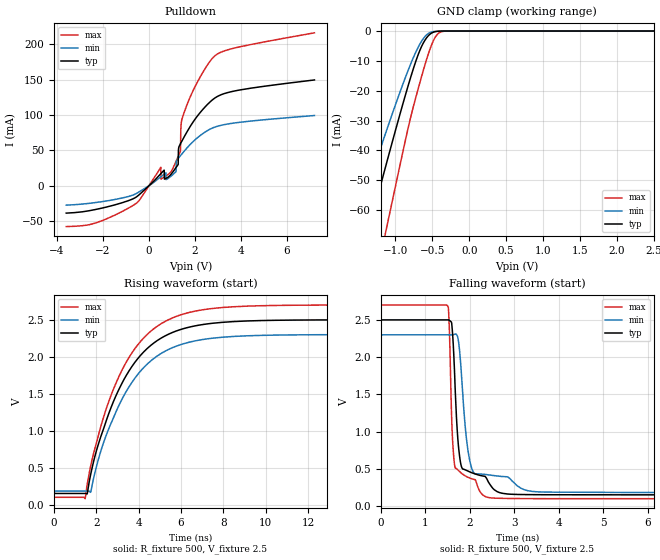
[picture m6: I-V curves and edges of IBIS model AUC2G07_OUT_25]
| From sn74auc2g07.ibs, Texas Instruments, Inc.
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[Model]   AUC2G07_OUT_25
Model_type  Open_drain
Enable   Active-Low
Vref =   2.5
Rref =   500
Cref =   30p
Vmeas =   1.25
| variable   typ   min   max
C_comp   2.87pF   2.41pF   3.25pF
| C_pulldown   5.35pF   1.05pF   13.60pF
| C_tri-state   2.87pF   2.41pF   3.25pF
[Temperature Range]   40   100   -40
| Ambient temperature   25   85   -40
[Voltage range]   2.5   2.3   2.7
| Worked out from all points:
|   slope of the pulldown table from 0 to 0.375 V, typ, clamps not added: 31 ohm
|   GND clamp passes 1 mA (typ) near -0.53 V on its own axis
|   rising waveform, R_fixture 500, V_fixture 2.5: 20-80 % time 2.22ns typ, 2.22ns min, 2.2ns max; typ from 0.154 V to 2.5 V
|   falling waveform, R_fixture 500, V_fixture 2.5: 20-80 % time 142ps typ, 202ps min, 95.6ps max; typ from 2.5 V to 0.154 V
[GND Clamp]
| AUC2G07_OUT_25
|   Voltage   I(typ)   I(min)   I(max)
-3.6V     -279.3mA   -228.7mA   -348mA
-1.585V   -87.68mA   -68.18mA   -119.7mA
-1.53V    -82.49mA   -63.96mA   -113.4mA
-1.34V    -64.62mA   -49.54mA   -91.44mA
-1.16V    -47.9mA    -36.19mA   -70.6mA
-1.11V    -43.3mA    -32.56mA   -64.8mA
-730mV    -10.56mA   -7.384mA   -22.79mA
-630mV    -4.374mA   -2.805mA   -13.86mA
-530mV    -1.024mA   -505.6uA   -5.921mA
-440mV    -130.5uA   -65.28uA   -1.345mA
-340mV    -7.443uA   -5.464uA   -72.36uA
2.5V      609.9pA    770.4pA    903.3pA
[Pulldown]
| AUC2G07_OUT_25
|   Voltage   I(typ)   I(min)   I(max)
-3.6V     -38.75mA   -27.46mA   -57.79mA
-1.19V    -24.29mA   -17.54mA   -36.85mA
515mV     17.02mA    12.57mA    25.99mA
520mV     17.2mA     12.7mA     9.298mA
930mV     15.04mA    12.66mA    18.59mA
1.27V     30.04mA    38.39mA    41.38mA
1.285V    51.79mA    39.01mA    42.52mA
1.37V     59.36mA    42.45mA    48.97mA
1.41V     61.79mA    44.06mA    89.97mA
1.645V    75.61mA    53.07mA    113.7mA
2.89V     124.5mA    83.14mA    184.2mA
7.2V      149.5mA    99.24mA    216.2mA
[Ramp]
| AUC2G07_OUT_25
| variable   typ   min   max
dV/dt_r   1.41/2.22E-09   1.28/2.22E-09   1.57/2.20E-09
dV/dt_f   1.41/1.45E-10   1.28/2.07E-10   1.56/9.72E-11
R_load = 500
[Rising Waveform]
| AUC2G07_OUT_25
R_fixture =   500
C_fixture =   0
L_fixture =   0
V_fixture =   2.5
V_fixture_min = 2.3
V_fixture_max = 2.7
|   Time   V(typ)   V(min)   V(max)
0s        154.5mV    186.3mV    102.6mV
1.475ns   154.2mV    186.3mV    83.61mV
1.575ns   149.7mV    186.3mV    275.2mV
1.74ns    412.2mV    176mV      527mV
2.21ns    916.1mV    720.5mV    1.052V
3.165ns   1.614V     1.399V     1.79V
4.255ns   2.069V     1.858V     2.259V
5.62ns    2.33V      2.125V     2.527V
9.12ns    2.483V     2.283V     2.683V
21.8ns    2.499V     2.3V       2.7V
[Falling Waveform]
| AUC2G07_OUT_25
R_fixture =   500
C_fixture =   0
L_fixture =   0
V_fixture =   2.5
V_fixture_min = 2.3
V_fixture_max = 2.7
|   Time   V(typ)   V(min)   V(max)
0s        2.5V       2.3V       2.7V
1.52ns    2.5V       2.3V       2.673V
1.605ns   2.4V       2.3V       1.037V
1.67ns    1.652V     2.309V     527.3mV
1.735ns   902.9mV    2.262V     488.9mV
1.82ns    525.9mV    1.73V      442.2mV
2.03ns    455.3mV    543.9mV    373.5mV
2.42ns    327.9mV    422.6mV    118.7mV
3.715ns   155.7mV    190.8mV    103.1mV
21.8ns    154.5mV    186.3mV    102.6mV
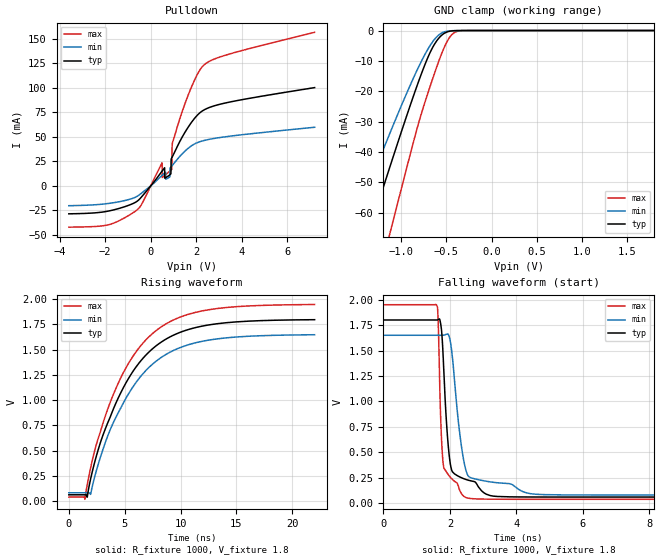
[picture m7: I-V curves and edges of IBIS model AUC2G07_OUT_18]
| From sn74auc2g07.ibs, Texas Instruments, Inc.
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[Model]   AUC2G07_OUT_18
Model_type  Open_drain
Enable   Active-Low
Vref =   1.8
Rref =   1000
Cref =   30p
Vmeas =   0.9
| variable   typ   min   max
C_comp   2.97pF   2.53pF   3.26pF
| C_pulldown   4.74pF   0.72pF   14.09pF
| C_tri-state   2.97pF   2.53pF   3.26pF
[Temperature Range]   40   100   -40
| Ambient temperature   25   85   -40
[Voltage range]   1.8   1.65   1.95
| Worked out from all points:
|   slope of the pulldown table from 0 to 0.27 V, typ, clamps not added: 34.3 ohm
|   GND clamp passes 1 mA (typ) near -0.53 V on its own axis
|   rising waveform, R_fixture 1000, V_fixture 1.8: 20-80 % time 4.56ns typ, 4.56ns min, 4.51ns max; typ from 0.061 V to 1.8 V
|   falling waveform, R_fixture 1000, V_fixture 1.8: 20-80 % time 207ps typ, 327ps min, 123ps max; typ from 1.8 V to 0.061 V
[GND Clamp]
| AUC2G07_OUT_18
|   Voltage   I(typ)   I(min)   I(max)
-3.6V     -279.3mA   -228.7mA   -348mA
-1.555V   -84.85mA   -65.88mA   -116.2mA
-1.365V   -66.96mA   -51.42mA   -94.33mA
-1.32V    -62.75mA   -48.04mA   -89.13mA
-1.125V   -44.68mA   -33.64mA   -66.54mA
-815mV    -17.24mA   -12.36mA   -31.12mA
-685mV    -7.459mA   -5.101mA   -18.71mA
-610mV    -3.475mA   -2.138mA   -12.15mA
-530mV    -1.024mA   -505.6uA   -5.921mA
-425mV    -87.51uA   -45.91uA   -946.5uA
-295mV    -1.872uA   -1.583uA   -13.35uA
1.8V      394.7pA    569.4pA    453.3pA
[Pulldown]
| AUC2G07_OUT_18
|   Voltage   I(typ)   I(min)   I(max)
-3.6V     -28.49mA   -20.22mA   -42.08mA
-690mV    -16.99mA   -11.76mA   -26.03mA
495mV     14.95mA    10.62mA    23.51mA
505mV     15.26mA    10.84mA    8.468mA
840mV     11.22mA    9.16mA     14.98mA
885mV     12.27mA    19.08mA    15.87mA
895mV     26.23mA    19.35mA    16.1mA
915mV     28.13mA    19.9mA     16.6mA
950mV     29.67mA    20.88mA    43.17mA
1.25V     43.93mA    29.26mA    66.37mA
2.385V    77.89mA    46.46mA    124mA
7.2V      100.1mA    59.68mA    156.4mA
[Ramp]
| AUC2G07_OUT_18
| variable   typ   min   max
dV/dt_r   1.06/4.56E-09   0.95/4.56E-09   1.16/4.51E-09
dV/dt_f   1.05/2.16E-10   0.95/3.31E-10   1.15/1.27E-10
R_load = 1000
[Rising Waveform]
| AUC2G07_OUT_18
R_fixture =   1000
C_fixture =   0
L_fixture =   0
V_fixture =   1.8
V_fixture_min = 1.65
V_fixture_max = 1.95
|   Time   V(typ)   V(min)   V(max)
0s        61.05mV    81.2mV     38.68mV
1.44ns    61.05mV    81.2mV     16.47mV
1.645ns   38.68mV    81.21mV    158mV
1.945ns   214.7mV    65.34mV    323.9mV
3.185ns   690.3mV    553.1mV    814.6mV
4.58ns    1.056V     906mV      1.204V
6.09ns    1.338V     1.185V     1.488V
7.815ns   1.537V     1.385V     1.688V
12.51ns   1.744V     1.593V     1.894V
22ns      1.796V     1.647V     1.946V
[Falling Waveform]
| AUC2G07_OUT_18
R_fixture =   1000
C_fixture =   0
L_fixture =   0
V_fixture =   1.8
V_fixture_min = 1.65
V_fixture_max = 1.95
|   Time   V(typ)   V(min)   V(max)
0s        1.8V       1.65V      1.95V
1.61ns    1.8V       1.65V      1.939V
1.65ns    1.804V     1.65V      1.751V
1.735ns   1.734V     1.65V      727.5mV
1.805ns   1.385V     1.651V     371.2mV
2.025ns   363.8mV    1.565V     251.7mV
2.305ns   257.3mV    661.7mV    120.1mV
2.51ns    230.8mV    296mV      53.25mV
4.79ns    61.32mV    85.25mV    38.73mV
22ns      61.05mV    81.2mV     38.68mV
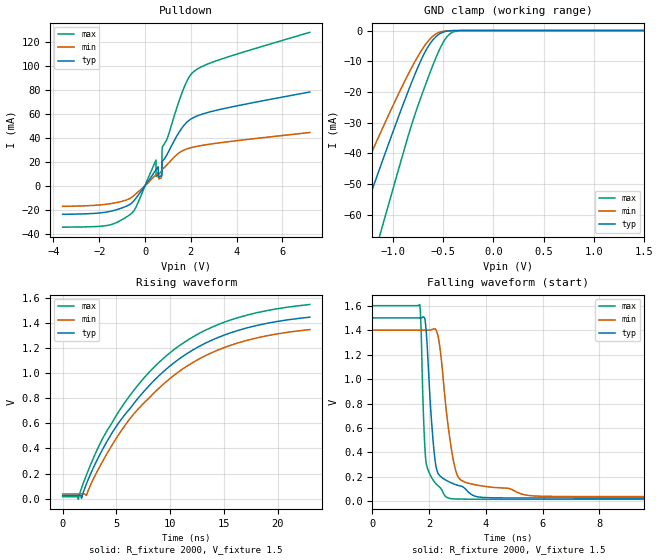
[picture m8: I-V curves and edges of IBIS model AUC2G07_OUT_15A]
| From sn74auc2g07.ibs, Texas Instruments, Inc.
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[Model]   AUC2G07_OUT_15A
Model_type  Open_drain
Enable   Active-Low
Vref =   1.5
Rref =   2000
Cref =   15p
Vmeas =   0.75
| variable   typ   min   max
C_comp   3.01pF   2.60pF   3.26pF
| C_pulldown   4.79pF   1.98pF   12.89pF
| C_tri-state   3.01pF   2.60pF   3.26pF
[Temperature Range]   40   100   -40
| Ambient temperature   25   85   -40
[Voltage range]   1.5   1.4   1.6
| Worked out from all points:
|   slope of the pulldown table from 0 to 0.225 V, typ, clamps not added: 37.3 ohm
|   GND clamp passes 1 mA (typ) near -0.53 V on its own axis
|   rising waveform, R_fixture 2000, V_fixture 1.5: 20-80 % time 8.47ns typ, 8.39ns min, 8.37ns max; typ from 0.027 V to 1.45 V
|   falling waveform, R_fixture 2000, V_fixture 1.5: 20-80 % time 270ps typ, 432ps min, 152ps max; typ from 1.5 V to 0.027 V
[GND Clamp]
| AUC2G07_OUT_15A
|   Voltage   I(typ)   I(min)   I(max)
-3.6V     -279.3mA   -228.7mA   -348mA
-1.535V   -82.96mA   -64.34mA   -113.9mA
-1.35V    -65.56mA   -50.29mA   -92.6mA
-1.15V    -46.98mA   -35.46mA   -69.44mA
-1.1V     -42.39mA   -31.84mA   -63.64mA
-825mV    -18.08mA   -12.98mA   -32.18mA
-685mV    -7.459mA   -5.101mA   -18.71mA
-560mV    -1.73mA    -927.3uA   -8.105mA
-495mV    -497.5uA   -233uA     -3.727mA
-430mV    -100.1uA   -51.64uA   -1.068mA
-305mV    -2.545uA   -2.096uA   -19.74uA
1.5V      322pA      494.6pA    331.6pA
[Pulldown]
| AUC2G07_OUT_15A
|   Voltage   I(typ)   I(min)   I(max)
-3.6V     -23.87mA   -17.26mA   -34.61mA
-1.565V   -21.6mA    -15.16mA   -32.85mA
-520mV    -13.36mA   -8.764mA   -21.72mA
480mV     13.33mA    9.224mA    21.44mA
485mV     13.46mA    9.315mA    7.619mA
720mV     8.537mA    6.727mA    11.81mA
735mV     8.725mA    13.39mA    12.06mA
745mV     18.83mA    13.54mA    29.66mA
760mV     20.34mA    13.77mA    32.32mA
1.73V     50.99mA    29.95mA    83.08mA
2.16V     57.23mA    32.4mA     95.69mA
7.2V      78.2mA     44.4mA     128mA
[Ramp]
| AUC2G07_OUT_15A
| variable   typ   min   max
dV/dt_r   0.86/8.49E-09   0.79/8.41E-09   0.93/8.39E-09
dV/dt_f   0.89/2.78E-10   0.82/4.39E-10   0.96/1.61E-10
R_load = 2000
[Rising Waveform]
| AUC2G07_OUT_15A
R_fixture =   2000
C_fixture =   0
L_fixture =   0
V_fixture =   1.5
V_fixture_min = 1.4
V_fixture_max = 1.6
|   Time   V(typ)   V(min)   V(max)
0s        27.17mV    38.78mV    16.4mV
1.46ns    27.17mV    38.78mV    -4.298mV
1.765ns   4.91mV     38.78mV    86.2mV
2.21ns    117.1mV    26.15mV    188.2mV
3.685ns   387.7mV    292.4mV    473.7mV
5.7ns     659.1mV    571.8mV    755.4mV
7.915ns   887.3mV    790.6mV    994mV
10.25ns   1.075V     974.9mV    1.179V
15.62ns   1.32V      1.221V     1.422V
23ns      1.445V     1.346V     1.546V
[Falling Waveform]
| AUC2G07_OUT_15A
R_fixture =   2000
C_fixture =   0
L_fixture =   0
V_fixture =   1.5
V_fixture_min = 1.4
V_fixture_max = 1.6
|   Time   V(typ)   V(min)   V(max)
0s        1.5V       1.4V       1.6V
1.67ns    1.5V       1.4V       1.61V
1.81ns    1.506V     1.4V       633.4mV
1.89ns    1.404V     1.4V       318mV
2.22ns    314.8mV    1.409V     149.6mV
2.375ns   210mV      1.264V     114.7mV
2.685ns   161.7mV    587.4mV    26.48mV
3.105ns   125.2mV    176mV      18.54mV
5.525ns   27.29mV    47.58mV    16.41mV
23ns      27.17mV    38.78mV    16.4mV
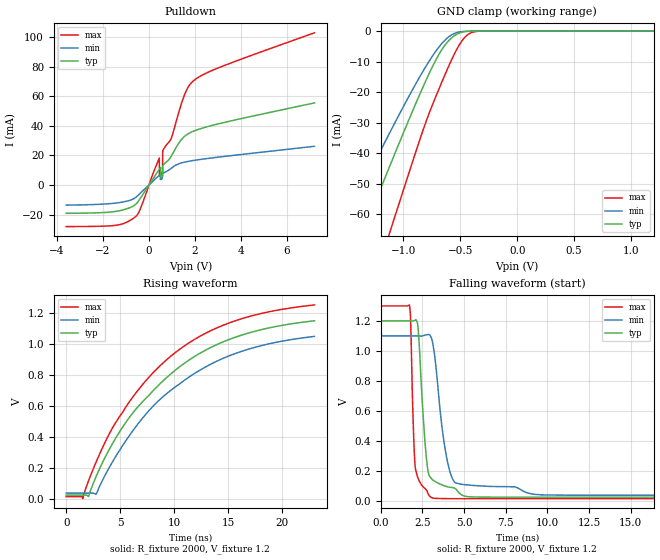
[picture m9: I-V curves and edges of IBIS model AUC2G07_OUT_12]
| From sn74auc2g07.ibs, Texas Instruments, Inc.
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[Model]   AUC2G07_OUT_12
Model_type  Open_drain
Enable   Active-Low
Vref =   1.2
Rref =   2000
Cref =   15p
Vmeas =   0.6
| variable   typ   min   max
C_comp   3.06pF   2.68pF   3.26pF
| C_pulldown   4.01pF   2.19pF   12.50pF
| C_tri-state   3.06pF   2.68pF   3.26pF
[Temperature Range]   40   100   -40
| Ambient temperature   25   85   -40
[Voltage range]   1.2   1.1   1.3
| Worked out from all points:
|   slope of the pulldown table from 0 to 0.18 V, typ, clamps not added: 42.4 ohm
|   GND clamp passes 1 mA (typ) near -0.53 V on its own axis
|   rising waveform, R_fixture 2000, V_fixture 1.2: 20-80 % time 8.55ns typ, 8.48ns min, 8.39ns max; typ from 0.024 V to 1.15 V
|   falling waveform, R_fixture 2000, V_fixture 1.2: 20-80 % time 414ps typ, 709ps min, 208ps max; typ from 1.2 V to 0.024 V
[GND Clamp]
| AUC2G07_OUT_12
|   Voltage   I(typ)   I(min)   I(max)
-3.6V     -279.3mA   -228.7mA   -348mA
-1.56V    -85.32mA   -66.26mA   -116.8mA
-1.51V    -80.6mA    -62.43mA   -111mA
-1.33V    -63.68mA   -48.79mA   -90.29mA
-1.125V   -44.68mA   -33.64mA   -66.54mA
-1.085V   -41.02mA   -30.76mA   -61.9mA
-825mV    -18.08mA   -12.98mA   -32.18mA
-690mV    -7.781mA   -5.339mA   -19.16mA
-570mV    -2.022mA   -1.117mA   -8.88mA
-435mV    -114.4uA   -58.08uA   -1.201mA
-315mV    -3.46uA    -2.767uA   -28.94uA
1.2V      258.8pA    425.9pA    238.4pA
[Pulldown]
| AUC2G07_OUT_12
|   Voltage   I(typ)   I(min)   I(max)
-3.6V     -19.18mA   -13.63mA   -28.17mA
-1.38V    -17.74mA   -12.12mA   -27.16mA
-535mV    -12.4mA    -7.82mA    -20.65mA
450mV     10.5mA     6.398mA    18.24mA
455mV     10.61mA    6.451mA    6.435mA
590mV     5.848mA    7.731mA    8.546mA
600mV     5.947mA    7.818mA    22.94mA
605mV     12.96mA    7.861mA    23.36mA
970mV     19.53mA    11.32mA    31.67mA
1.615V    33.73mA    15.67mA    63.55mA
1.985V    36.71mA    16.71mA    71.15mA
7.2V      55.55mA    26.19mA    103mA
[Ramp]
| AUC2G07_OUT_12
| variable   typ   min   max
dV/dt_r   0.68/8.56E-09   0.61/8.50E-09   0.75/8.40E-09
dV/dt_f   0.71/4.22E-10   0.64/7.14E-10   0.78/2.13E-10
R_load = 2000
[Rising Waveform]
| AUC2G07_OUT_12
R_fixture =   2000
C_fixture =   0
L_fixture =   0
V_fixture =   1.2
V_fixture_min = 1.1
V_fixture_max = 1.3
|   Time   V(typ)   V(min)   V(max)
0s        23.98mV    36.64mV    13.86mV
1.535ns   23.98mV    36.64mV    1.138mV
2.075ns   15.26mV    36.64mV    117.8mV
2.765ns   143.2mV    30.34mV    236.6mV
4.19ns    344.4mV    226.5mV    445.6mV
5.92ns    531.5mV    414.9mV    633.2mV
8.03ns    696mV      596.6mV    812.4mV
10.18ns   834.1mV    725.8mV    947.5mV
15.62ns   1.042V     936.4mV    1.148V
23ns      1.149V     1.048V     1.251V
[Falling Waveform]
| AUC2G07_OUT_12
R_fixture =   2000
C_fixture =   0
L_fixture =   0
V_fixture =   1.2
V_fixture_min = 1.1
V_fixture_max = 1.3
|   Time   V(typ)   V(min)   V(max)
0s        1.2V       1.1V       1.3V
1.725ns   1.2V       1.1V       1.305V
1.795ns   1.2V       1.1V       1.197V
2.01ns    1.202V     1.1V       331.1mV
2.185ns   1.193V     1.1V       168.8mV
2.715ns   313.3mV    1.107V     75.25mV
3.025ns   149.4mV    1.09V      22.48mV
3.875ns   97.72mV    337.7mV    14.46mV
4.495ns   79.94mV    118.9mV    14.02mV
23ns      23.98mV    36.65mV    13.86mV
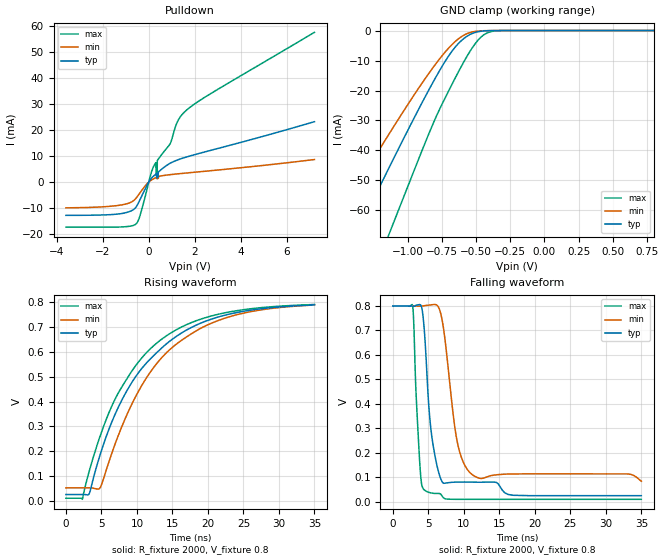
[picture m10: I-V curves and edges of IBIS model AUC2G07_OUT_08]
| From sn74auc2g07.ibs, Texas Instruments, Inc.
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[Model]   AUC2G07_OUT_08
Model_type  Open_drain
Enable   Active-Low
Vref =   0.8
Rref =   2000
Cref =   15p
Vmeas =   0.4
| variable   typ   min   max
C_comp   3.12pF   2.83pF   3.28pF
| C_pulldown   3.74pF   3.15pF   4.26pF
| C_tri-state   3.12pF   2.83pF   3.28pF
[Temperature Range]   40   100   -40
| Ambient temperature   25   85   -40
[Voltage range]   0.8   0.8   0.8
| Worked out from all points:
|   slope of the pulldown table from 0 to 0.12 V, typ, clamps not added: 77.1 ohm
|   GND clamp passes 1 mA (typ) near -0.53 V on its own axis
|   rising waveform, R_fixture 2000, V_fixture 0.8: 20-80 % time 9.6ns typ, 9.49ns min, 9.01ns max; typ from 0.025 V to 0.79 V
|   falling waveform, R_fixture 2000, V_fixture 0.8: 20-80 % time 1.42ns typ, 1.83ns min, 727ps max; typ from 0.8 V to 0.025 V
[GND Clamp]
| AUC2G07_OUT_08
|   Voltage   I(typ)   I(min)   I(max)
-3.6V     -279.3mA   -228.7mA   -348mA
-1.565V   -85.79mA   -66.64mA   -117.4mA
-1.35V    -65.56mA   -50.29mA   -92.6mA
-1.14V    -46.06mA   -34.73mA   -68.28mA
-1.1V     -42.39mA   -31.84mA   -63.64mA
-830mV    -18.49mA   -13.3mA    -32.72mA
-695mV    -8.11mA    -5.581mA   -19.61mA
-575mV    -2.179mA   -1.221mA   -9.275mA
-505mV    -618.6uA   -292.2uA   -4.307mA
-450mV    -169uA     -82.44uA   -1.67mA
-330mV    -5.484uA   -4.173uA   -50.52uA
800mV     186.8pA    341.4pA    147.7pA
[Pulldown]
| AUC2G07_OUT_08
|   Voltage   I(typ)   I(min)   I(max)
-3.6V     -12.84mA   -9.953mA   -17.38mA
-570mV    -9.824mA   -6.369mA   -16.25mA
-385mV    -6.858mA   -4.174mA   -13.02mA
190mV     2.176mA    1.163mA    5.632mA
310mV     3.079mA    1.693mA    7.502mA
315mV     3.117mA    1.714mA    2.469mA
365mV     1.692mA    1.285mA    2.781mA
370mV     1.723mA    1.302mA    8.254mA
925mV     7.223mA    2.844mA    14.73mA
1.22V     8.419mA    3.123mA    22.74mA
1.49V     9.254mA    3.359mA    26.43mA
7.2V      23.27mA    8.675mA    57.71mA
[Ramp]
| AUC2G07_OUT_08
| variable   typ   min   max
dV/dt_r   0.46/9.59E-09   0.45/9.48E-09   0.47/9.01E-09
dV/dt_f   0.47/1.42E-09   0.43/1.84E-09   0.48/7.31E-10
R_load = 2000
[Rising Waveform]
| AUC2G07_OUT_08
R_fixture =   2000
C_fixture =   0
L_fixture =   0
V_fixture =   0.8
V_fixture_min = 0.8
V_fixture_max = 0.8
|   Time   V(typ)   V(min)   V(max)
0s        25.46mV    52.25mV    10.6mV
2.31ns    25.49mV    52.26mV    6.298mV
3.285ns   29.33mV    52.57mV    120.3mV
4.785ns   183.5mV    51.87mV    258.7mV
6.63ns    329.7mV    206.1mV    393.1mV
8.59ns    444.5mV    347.7mV    492.3mV
13.21ns   609.2mV    568.5mV    646mV
16.99ns   689mV      661.2mV    710.5mV
21.83ns   744.6mV    731.3mV    754.9mV
34.99ns   790.1mV    789.9mV    791.8mV
[Falling Waveform]
| AUC2G07_OUT_08
R_fixture =   2000
C_fixture =   0
L_fixture =   0
V_fixture =   0.8
V_fixture_min = 0.8
V_fixture_max = 0.8
|   Time   V(typ)   V(min)   V(max)
0s        800mV      800mV      800mV
2.8ns     799.3mV    800mV      797.9mV
3.275ns   802.7mV    799.9mV    441.2mV
3.785ns   805.8mV    799.2mV    162.3mV
4.41ns    709.5mV    801mV      49.33mV
5.41ns    285.8mV    804.9mV    36.61mV
7.075ns   77.27mV    720.7mV    18.42mV
9.035ns   80.93mV    251mV      10.66mV
11.14ns   80.85mV    112.4mV    10.6mV
34.99ns   25.47mV    84.58mV    10.6mV
